! (c) 2009  Infineon Technologies AG, Munich
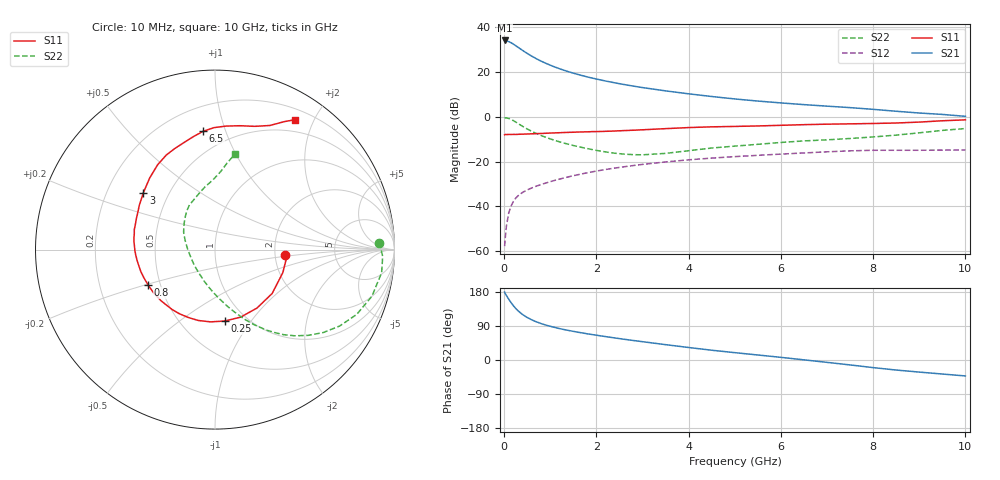
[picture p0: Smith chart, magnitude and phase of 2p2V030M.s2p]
! Infineon Technologies  Discrete & RF Semiconductors
! BFP420
! VCE =  2.0 V,  IC =  30 mA
! Common Emitter S-Parameters:  Nov 2009
# GHz  S  MA  R  50
!  f  S11  S21  S12  S22
! GHz  MAG  ANG  MAG  ANG  MAG  ANG  MAG  ANG
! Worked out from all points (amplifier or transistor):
!   46 points, 10 MHz to 10 GHz, reference 50 ohm
!   highest |S21| = 33.9 dB at 10 MHz (marker M1)
!   |S21| within 3 dB of that: start of sweep to 298.9 MHz
!   unconditionally stable (mu >= 1): 1.505 GHz to end of sweep
!   at 300 MHz: K = 0.40, MSG = 33.1 dB, |S12| = -35.3 dB
!   at 1.7 GHz: K = 1.04, MAG = 20.7 dB, |S12| = -25.4 dB
!   at 10 GHz: K = 1.06, MAG = 6.0 dB, |S12| = -14.8 dB
!   lowest NFmin = 1.51 dB at 900 MHz
!   S11 on the Smith chart (normalised r, x): 10 MHz: 2.28, -0.16; 250 MHz: 0.80, -0.76; 800 MHz: 0.43, -0.21; 3 GHz: 0.36, +0.31; 6.5 GHz: 0.36, +0.84; 10 GHz: 0.34, +1.74
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0.01  0.3934 -4.3  49.82 179.4  0.0013 110.1  0.9156 2.4
0.02  0.4004 -7.8  48.8 176.1  0.0018 94.4  0.9351 -2.3
0.05  0.399 -18.8  48.38 170.0  0.0037 85.7  0.9373 -7.9
0.1  0.4015 -37.5  46.94 160.3  0.0072 78.7  0.912 -16.6
0.15  0.401 -54.3  44.32 151.3  0.0102 73.5  0.868 -24.6
0.2  0.4025 -69.2  41.34 143.3  0.0129 69.7  0.8146 -31.5
0.25  0.4017 -82.3  38.12 136.2  0.0152 66.3  0.7594 -37.5
0.35  0.4058 -103.2  32.43 124.8  0.0189 61.7  0.6546 -47.2
0.4  0.4065 -111.6  29.92 120.0  0.0205 60.2  0.6091 -51.1
0.5  0.4105 -125.5  25.62 112.2  0.0233 58.4  0.5312 -57.5
0.6  0.4143 -136.3  22.21 105.8  0.0258 57.6  0.4696 -62.7
0.8  0.4216 -152.1  17.28 96.2  0.0307 57.1  0.3803 -70.9
1.2  0.4386 -172.3  11.69 82.9  0.0406 56.7  0.2748 -85.0
1.7  0.4567 171.3  8.178 71.3  0.0534 54.9  0.2043 -101.9
2.2  0.4708 158.5  6.22 61.7  0.0664 51.7  0.1635 -120.6
3  0.5095 141.6  4.445 48.3  0.0863 45.0  0.141 -157.9
3.5  0.5403 132.3  3.75 40.5  0.0979 40.3  0.1518 179.8
5.5  0.6202 106.4  2.224 13.2  0.1374 21.5  0.2419 133.9
6.5  0.6626 95.7  1.853 0.4  0.1552 12.1  0.2879 119.4
7  0.6794 90.5  1.713 -6.2  0.1645 7.2  0.3043 112.1
8.5  0.7216 72.1  1.318 -26.5  0.1781 -10.1  0.3874 91.9
10  0.8485 58.5  1.016 -42.1  0.1812 -21.3  0.5433 78.1
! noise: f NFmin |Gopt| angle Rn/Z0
0.9  1.51  0.26  -155  0.13
1.8  1.78  0.33  -142  0.14
2.4  1.96  0.3  -136  0.18
3  1.98  0.38  -127  0.2
4  2.11  0.47  -111  0.31
5  2.57  0.53  -94  0.51
6  3  0.57  -82  0.74
